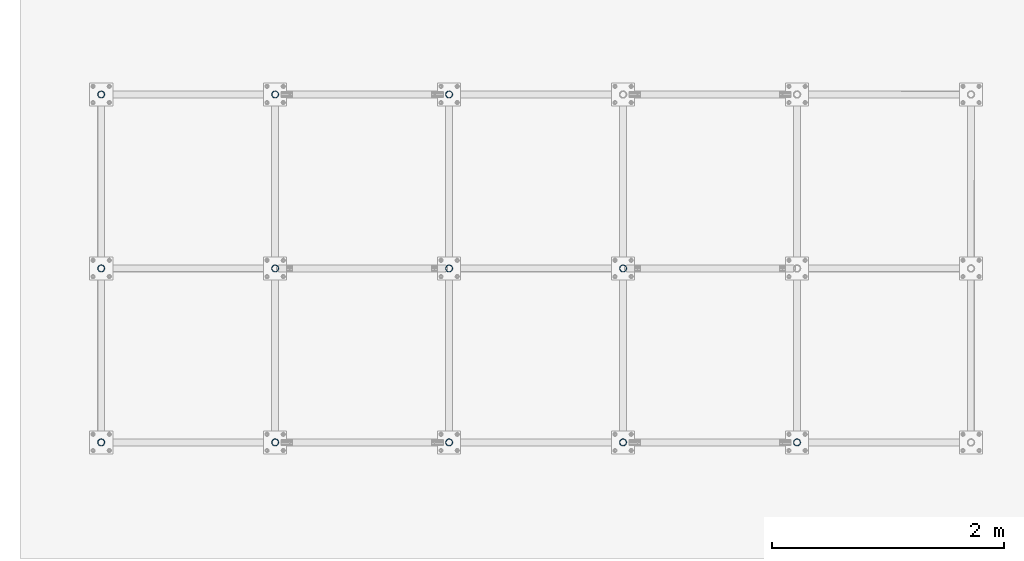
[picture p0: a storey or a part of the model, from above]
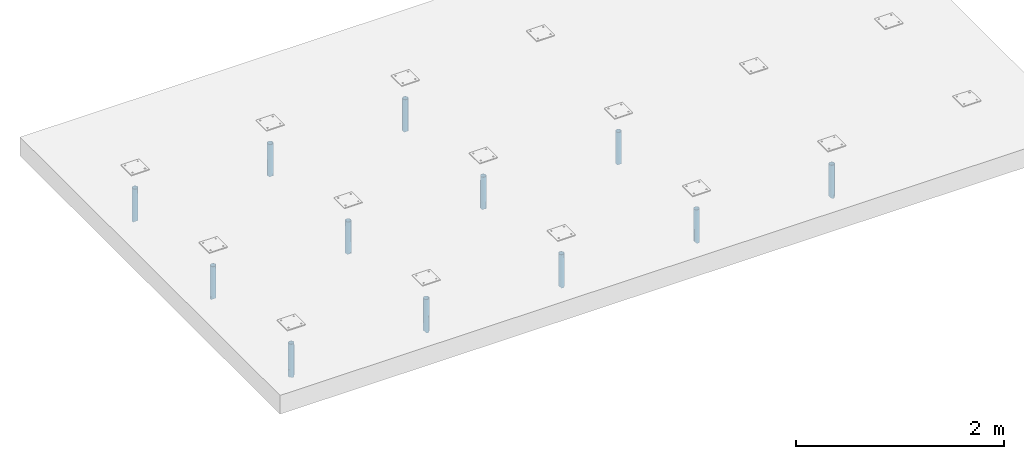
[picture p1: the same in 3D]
Properties of the parts of a building model (IFC2X3)

# File
Description: ViewDefinition[CoordinationView_V2.0]
File name: Modellbereich Deckenger?st_ifc2x3.ifc
Time: 2026-07-14T21:49:34
Organization: Landeshauptstadt M?nchen
Written by: IFC Toolkit 2.0.26.0
Made in: Advance Steel 2024

# IfcBuildingStorey, Default Storey
In: Struktur 1
Elevation: 0 mm

# IfcBeam: - (16)
In: Default Storey
Description: RO60.3X2.6; Material: S235JR
ProfileProperties - SectionFamily: Pipe nach DIN; Section: RO60.3X2.6

# IfcBeam: Gel?nder (3)
In: Default Storey
Description: RO60.3X2.6; Material: S235JR
Pset_BeamCommon - Slope: 0 deg; IsExternal: no; LoadBearing: no
ProfileProperties - SectionFamily: Pipe nach DIN; Section: RO60.3X2.6
Name | Reference | Span (mm)
Gel?nder | 4 | 1630.15
Gel?nder | 3 | 1700
Gel?nder | 2 | 1630.15

# IfcBeam: Girder (6)
In: Default Storey
Description: RO60.3X2.6; Material: S235JR
Pset_BeamCommon - Reference: 1; Span: 1299 mm; Slope: 0 deg; IsExternal: no; LoadBearing: no
ProfileProperties - SectionFamily: Pipe nach DIN; Section: RO60.3X2.6

# IfcBuildingElementProxy: - (228)
In: Default Storey
Name | Material
216 x  | Kein
12 x  | S235JR

# IfcColumn: - (18)
In: Default Storey
Description: RO60.3X2.6; Material: S235JR
ProfileProperties - SectionFamily: Pipe nach DIN; Section: RO60.3X2.6

# IfcMechanicalFastener: - (12)
In: Default Storey
NominalDiameter: 6 mm; NominalLength: 20 mm

# IfcPlate: - (36)
In: Default Storey
Description: -; Material: S235JR 10 mm
Pset_PlateCommon - IsExternal: no; LoadBearing: no
Name | Reference
18 x - | 5
18 x - | 109

# IfcSlab: -
In: Default Storey
Description: -; Material: Brettschichtholz BS11 220 mm
Pset_SlabCommon - Reference: nicht definiert; IsExternal: no; LoadBearing: no; Combustible: no; Compartmentation: no; PitchAngle: 0 deg
